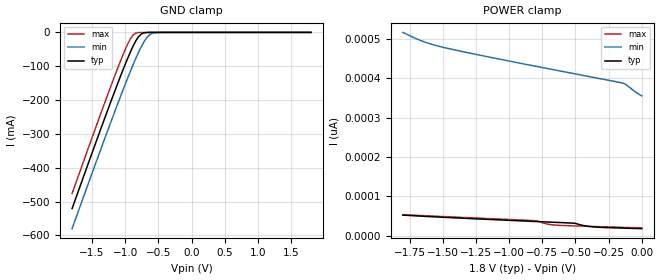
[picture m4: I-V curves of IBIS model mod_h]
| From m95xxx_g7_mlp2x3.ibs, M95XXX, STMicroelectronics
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|   Model mod_h
[Model]   mod_h
Model_type Input
Vinl   =   0.540V
Vinh   =   1.260V
C_comp   2.119pF   2.023pF   2.323pF
[Temperature Range]   25.0000   0.1050k   -40.0000
[Voltage Range]   1.8000V   1.7000V   2.0000V
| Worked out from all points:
|   GND clamp passes 1 mA (typ) near -0.70 V on its own axis
[GND_clamp]
|Voltage   I(typ)   I(min)   I(max)
-1.8V     -520.9mA   -580.3mA   -476.4mA
-1.2V     -196.3mA   -256.7mA   -150.7mA
-1.04V    -114.2mA   -173.8mA   -69.64mA
-960mV    -75.5mA    -133.8mA   -33.44mA
-880mV    -40.19mA   -95.27mA   -7.262mA
-800mV    -12.93mA   -59.45mA   -437.7uA
-760mV    -5.115mA   -43.21mA   -157.1uA
-720mV    -1.573mA   -28.76mA   -100.4uA
-640mV    -132.4uA   -8.366mA   -67.87uA
-560mV    -24.53uA   -1.273mA   -44.38uA
-480mV    -7.538uA   -153uA     -22.96uA
1.8V      15.87pA    456.8pA    13.84pA
[POWER_clamp]
|Voltage   I(typ)   I(min)   I(max)
-1.8V     52.4pA     516.1pA    53.47pA
-1.64V    49.32pA    492.2pA    50.9pA
-1.48V    46.57pA    476.9pA    48.43pA
-800mV    36.19pA    430.2pA    38.21pA
-740mV    35.32pA    426.3pA    31.92pA
-680mV    34.45pA    422.4pA    28.02pA
-520mV    31.98pA    412pA      25.1pA
-380mV    22.99pA    402.9pA    23.66pA
-140mV    19.37pA    387.1pA    21.23pA
-120mV    19.17pA    383.7pA    21.03pA
-40mV     18.37pA    363.1pA    20.22pA
0V        17.97pA    355.1pA    19.82pA
